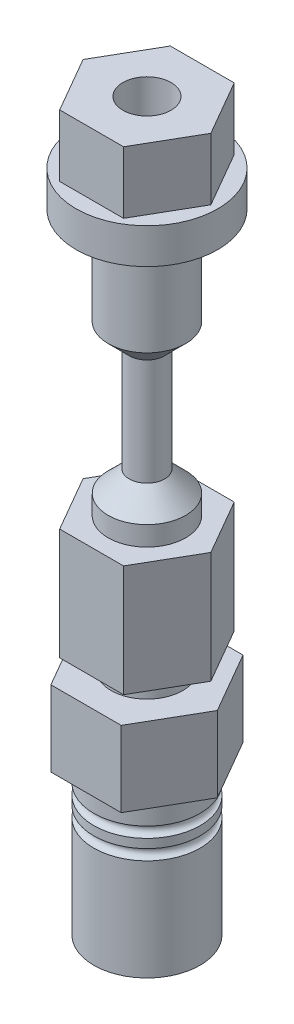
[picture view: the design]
ISO-10303-21;
HEADER;
FILE_DESCRIPTION(('STEP AP214'),'2;1');
FILE_NAME('part.step','',(''),(''),'','','');
FILE_SCHEMA(('AUTOMOTIVE_DESIGN { 1 0 10303 214 1 1 1 1 }'));
ENDSEC;
DATA;
#1=APPLICATION_CONTEXT('core data for automotive mechanical design processes');
#2=APPLICATION_PROTOCOL_DEFINITION('international standard','automotive_design',2000,#1);
#3=PRODUCT_CONTEXT('',#1,'mechanical');
#4=PRODUCT('Part','Part','',(#3));
#5=PRODUCT_RELATED_PRODUCT_CATEGORY('part','',(#4));
#6=PRODUCT_DEFINITION_FORMATION('','',#4);
#7=PRODUCT_DEFINITION_CONTEXT('part definition',#1,'design');
#8=PRODUCT_DEFINITION('design','',#6,#7);
#9=PRODUCT_DEFINITION_SHAPE('','',#8);
#10=(LENGTH_UNIT() NAMED_UNIT(*) SI_UNIT(.MILLI.,.METRE.));
#11=(NAMED_UNIT(*) PLANE_ANGLE_UNIT() SI_UNIT($,.RADIAN.));
#12=(NAMED_UNIT(*) SI_UNIT($,.STERADIAN.) SOLID_ANGLE_UNIT());
#13=UNCERTAINTY_MEASURE_WITH_UNIT(LENGTH_MEASURE(1.E-05),#10,'distance_accuracy_value','');
#14=(GEOMETRIC_REPRESENTATION_CONTEXT(3) GLOBAL_UNCERTAINTY_ASSIGNED_CONTEXT((#13)) GLOBAL_UNIT_ASSIGNED_CONTEXT((#10,
#11,#12)) REPRESENTATION_CONTEXT('',''));
#15=CARTESIAN_POINT('',(0.,0.,0.));
#16=DIRECTION('',(0.,0.,1.));
#17=DIRECTION('',(1.,0.,0.));
#18=AXIS2_PLACEMENT_3D('',#15,#16,#17);
#19=CARTESIAN_POINT('',(9.16543552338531,-59.182,0.));
#20=DIRECTION('',(-0.866025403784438,0.,-0.5));
#21=DIRECTION('',(-0.5,0.,0.866025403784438));
#22=AXIS2_PLACEMENT_3D('',#19,#20,#21);
#23=PLANE('',#22);
#24=DIRECTION('',(-0.5,0.,0.866025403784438));
#25=VECTOR('',#24,1.);
#26=CARTESIAN_POINT('',(9.16543552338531,-43.18,0.));
#27=LINE('',#26,#25);
#28=CARTESIAN_POINT('',(9.16543552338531,-43.18,0.));
#29=VERTEX_POINT('',#28);
#30=CARTESIAN_POINT('',(4.58271776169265,-43.18,7.9375));
#31=VERTEX_POINT('',#30);
#32=EDGE_CURVE('E135',#29,#31,#27,.T.);
#33=ORIENTED_EDGE('',*,*,#32,.T.);
#34=DIRECTION('',(0.,1.,0.));
#35=VECTOR('',#34,1.);
#36=CARTESIAN_POINT('',(4.58271776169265,-59.182,7.9375));
#37=LINE('',#36,#35);
#38=CARTESIAN_POINT('',(4.58271776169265,-59.182,7.9375));
#39=VERTEX_POINT('',#38);
#40=EDGE_CURVE('E153',#39,#31,#37,.T.);
#41=ORIENTED_EDGE('',*,*,#40,.F.);
#42=DIRECTION('',(-0.5,0.,0.866025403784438));
#43=VECTOR('',#42,1.);
#44=CARTESIAN_POINT('',(9.16543552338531,-59.182,0.));
#45=LINE('',#44,#43);
#46=CARTESIAN_POINT('',(9.16543552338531,-59.182,0.));
#47=VERTEX_POINT('',#46);
#48=EDGE_CURVE('E146',#47,#39,#45,.T.);
#49=ORIENTED_EDGE('',*,*,#48,.F.);
#50=DIRECTION('',(0.,1.,0.));
#51=VECTOR('',#50,1.);
#52=CARTESIAN_POINT('',(9.16543552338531,-59.182,0.));
#53=LINE('',#52,#51);
#54=EDGE_CURVE('E131',#47,#29,#53,.T.);
#55=ORIENTED_EDGE('',*,*,#54,.T.);
#56=EDGE_LOOP('',(#33,#41,#49,#55));
#57=FACE_BOUND('',#56,.T.);
#58=ADVANCED_FACE('F45',(#57),#23,.F.);
#59=CARTESIAN_POINT('',(4.58271776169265,-59.182,7.9375));
#60=DIRECTION('',(0.,0.,-1.));
#61=DIRECTION('',(-1.,0.,0.));
#62=AXIS2_PLACEMENT_3D('',#59,#60,#61);
#63=PLANE('',#62);
#64=DIRECTION('',(-1.,0.,0.));
#65=VECTOR('',#64,1.);
#66=CARTESIAN_POINT('',(4.58271776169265,-43.18,7.9375));
#67=LINE('',#66,#65);
#68=CARTESIAN_POINT('',(-4.58271776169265,-43.18,7.9375));
#69=VERTEX_POINT('',#68);
#70=EDGE_CURVE('E138',#31,#69,#67,.T.);
#71=ORIENTED_EDGE('',*,*,#70,.T.);
#72=DIRECTION('',(0.,1.,0.));
#73=VECTOR('',#72,1.);
#74=CARTESIAN_POINT('',(-4.58271776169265,-59.182,7.9375));
#75=LINE('',#74,#73);
#76=CARTESIAN_POINT('',(-4.58271776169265,-59.182,7.9375));
#77=VERTEX_POINT('',#76);
#78=EDGE_CURVE('E150',#77,#69,#75,.T.);
#79=ORIENTED_EDGE('',*,*,#78,.F.);
#80=DIRECTION('',(-1.,0.,0.));
#81=VECTOR('',#80,1.);
#82=CARTESIAN_POINT('',(4.58271776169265,-59.182,7.9375));
#83=LINE('',#82,#81);
#84=EDGE_CURVE('E101',#39,#77,#83,.T.);
#85=ORIENTED_EDGE('',*,*,#84,.F.);
#86=ORIENTED_EDGE('',*,*,#40,.T.);
#87=EDGE_LOOP('',(#71,#79,#85,#86));
#88=FACE_BOUND('',#87,.T.);
#89=ADVANCED_FACE('F174',(#88),#63,.F.);
#90=CARTESIAN_POINT('',(-4.58271776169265,-59.182,7.9375));
#91=DIRECTION('',(0.866025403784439,0.,-0.5));
#92=DIRECTION('',(-0.5,0.,-0.866025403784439));
#93=AXIS2_PLACEMENT_3D('',#90,#91,#92);
#94=PLANE('',#93);
#95=DIRECTION('',(-0.5,0.,-0.866025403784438));
#96=VECTOR('',#95,1.);
#97=CARTESIAN_POINT('',(-4.58271776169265,-43.18,7.9375));
#98=LINE('',#97,#96);
#99=CARTESIAN_POINT('',(-9.16543552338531,-43.18,0.));
#100=VERTEX_POINT('',#99);
#101=EDGE_CURVE('E141',#69,#100,#98,.T.);
#102=ORIENTED_EDGE('',*,*,#101,.T.);
#103=DIRECTION('',(0.,1.,0.));
#104=VECTOR('',#103,1.);
#105=CARTESIAN_POINT('',(-9.16543552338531,-59.182,0.));
#106=LINE('',#105,#104);
#107=CARTESIAN_POINT('',(-9.16543552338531,-59.182,0.));
#108=VERTEX_POINT('',#107);
#109=EDGE_CURVE('E126',#108,#100,#106,.T.);
#110=ORIENTED_EDGE('',*,*,#109,.F.);
#111=DIRECTION('',(-0.5,0.,-0.866025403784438));
#112=VECTOR('',#111,1.);
#113=CARTESIAN_POINT('',(-4.58271776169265,-59.182,7.9375));
#114=LINE('',#113,#112);
#115=EDGE_CURVE('E117',#77,#108,#114,.T.);
#116=ORIENTED_EDGE('',*,*,#115,.F.);
#117=ORIENTED_EDGE('',*,*,#78,.T.);
#118=EDGE_LOOP('',(#102,#110,#116,#117));
#119=FACE_BOUND('',#118,.T.);
#120=ADVANCED_FACE('F179',(#119),#94,.F.);
#121=CARTESIAN_POINT('',(-9.16543552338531,-59.182,0.));
#122=DIRECTION('',(0.866025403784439,0.,0.5));
#123=DIRECTION('',(0.5,0.,-0.866025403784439));
#124=AXIS2_PLACEMENT_3D('',#121,#122,#123);
#125=PLANE('',#124);
#126=DIRECTION('',(0.5,0.,-0.866025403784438));
#127=VECTOR('',#126,1.);
#128=CARTESIAN_POINT('',(-9.16543552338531,-43.18,0.));
#129=LINE('',#128,#127);
#130=CARTESIAN_POINT('',(-4.58271776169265,-43.18,-7.93749999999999));
#131=VERTEX_POINT('',#130);
#132=EDGE_CURVE('E125',#100,#131,#129,.T.);
#133=ORIENTED_EDGE('',*,*,#132,.T.);
#134=DIRECTION('',(0.,1.,0.));
#135=VECTOR('',#134,1.);
#136=CARTESIAN_POINT('',(-4.58271776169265,-59.182,-7.93749999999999));
#137=LINE('',#136,#135);
#138=CARTESIAN_POINT('',(-4.58271776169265,-59.182,-7.93749999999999));
#139=VERTEX_POINT('',#138);
#140=EDGE_CURVE('E122',#139,#131,#137,.T.);
#141=ORIENTED_EDGE('',*,*,#140,.F.);
#142=DIRECTION('',(0.5,0.,-0.866025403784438));
#143=VECTOR('',#142,1.);
#144=CARTESIAN_POINT('',(-9.16543552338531,-59.182,0.));
#145=LINE('',#144,#143);
#146=EDGE_CURVE('E111',#108,#139,#145,.T.);
#147=ORIENTED_EDGE('',*,*,#146,.F.);
#148=ORIENTED_EDGE('',*,*,#109,.T.);
#149=EDGE_LOOP('',(#133,#141,#147,#148));
#150=FACE_BOUND('',#149,.T.);
#151=ADVANCED_FACE('F123',(#150),#125,.F.);
#152=CARTESIAN_POINT('',(-4.58271776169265,-59.182,-7.93749999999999));
#153=DIRECTION('',(0.,0.,1.));
#154=DIRECTION('',(1.,0.,0.));
#155=AXIS2_PLACEMENT_3D('',#152,#153,#154);
#156=PLANE('',#155);
#157=DIRECTION('',(1.,0.,0.));
#158=VECTOR('',#157,1.);
#159=CARTESIAN_POINT('',(-4.58271776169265,-43.18,-7.93749999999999));
#160=LINE('',#159,#158);
#161=CARTESIAN_POINT('',(4.58271776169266,-43.18,-7.93749999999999));
#162=VERTEX_POINT('',#161);
#163=EDGE_CURVE('E86',#131,#162,#160,.T.);
#164=ORIENTED_EDGE('',*,*,#163,.T.);
#165=DIRECTION('',(0.,1.,0.));
#166=VECTOR('',#165,1.);
#167=CARTESIAN_POINT('',(4.58271776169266,-59.182,-7.93749999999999));
#168=LINE('',#167,#166);
#169=CARTESIAN_POINT('',(4.58271776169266,-59.182,-7.93749999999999));
#170=VERTEX_POINT('',#169);
#171=EDGE_CURVE('E127',#170,#162,#168,.T.);
#172=ORIENTED_EDGE('',*,*,#171,.F.);
#173=DIRECTION('',(1.,0.,0.));
#174=VECTOR('',#173,1.);
#175=CARTESIAN_POINT('',(-4.58271776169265,-59.182,-7.93749999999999));
#176=LINE('',#175,#174);
#177=EDGE_CURVE('E115',#139,#170,#176,.T.);
#178=ORIENTED_EDGE('',*,*,#177,.F.);
#179=ORIENTED_EDGE('',*,*,#140,.T.);
#180=EDGE_LOOP('',(#164,#172,#178,#179));
#181=FACE_BOUND('',#180,.T.);
#182=ADVANCED_FACE('F129',(#181),#156,.F.);
#183=CARTESIAN_POINT('',(4.58271776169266,-59.182,-7.93749999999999));
#184=DIRECTION('',(-0.866025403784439,0.,0.5));
#185=DIRECTION('',(0.5,0.,0.866025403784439));
#186=AXIS2_PLACEMENT_3D('',#183,#184,#185);
#187=PLANE('',#186);
#188=DIRECTION('',(0.5,0.,0.866025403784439));
#189=VECTOR('',#188,1.);
#190=CARTESIAN_POINT('',(4.58271776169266,-43.18,-7.93749999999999));
#191=LINE('',#190,#189);
#192=EDGE_CURVE('E92',#162,#29,#191,.T.);
#193=ORIENTED_EDGE('',*,*,#192,.T.);
#194=ORIENTED_EDGE('',*,*,#54,.F.);
#195=DIRECTION('',(0.5,0.,0.866025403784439));
#196=VECTOR('',#195,1.);
#197=CARTESIAN_POINT('',(4.58271776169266,-59.182,-7.93749999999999));
#198=LINE('',#197,#196);
#199=EDGE_CURVE('E62',#170,#47,#198,.T.);
#200=ORIENTED_EDGE('',*,*,#199,.F.);
#201=ORIENTED_EDGE('',*,*,#171,.T.);
#202=EDGE_LOOP('',(#193,#194,#200,#201));
#203=FACE_BOUND('',#202,.T.);
#204=ADVANCED_FACE('F163',(#203),#187,.F.);
#205=CARTESIAN_POINT('',(0.,-59.182,0.));
#206=DIRECTION('',(0.,-1.,0.));
#207=DIRECTION('',(0.,0.,-1.));
#208=AXIS2_PLACEMENT_3D('',#205,#206,#207);
#209=PLANE('',#208);
#210=CARTESIAN_POINT('',(0.,-59.182,0.));
#211=DIRECTION('',(0.,-1.,0.));
#212=DIRECTION('',(0.,0.,-1.));
#213=AXIS2_PLACEMENT_3D('',#210,#211,#212);
#214=CIRCLE('',#213,5.04464607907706);
#215=CARTESIAN_POINT('',(0.,-59.182,-5.04464607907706));
#216=VERTEX_POINT('',#215);
#217=EDGE_CURVE('E54',#216,#216,#214,.T.);
#218=ORIENTED_EDGE('',*,*,#217,.F.);
#219=EDGE_LOOP('',(#218));
#220=FACE_BOUND('',#219,.T.);
#221=ORIENTED_EDGE('',*,*,#48,.T.);
#222=ORIENTED_EDGE('',*,*,#84,.T.);
#223=ORIENTED_EDGE('',*,*,#115,.T.);
#224=ORIENTED_EDGE('',*,*,#146,.T.);
#225=ORIENTED_EDGE('',*,*,#177,.T.);
#226=ORIENTED_EDGE('',*,*,#199,.T.);
#227=EDGE_LOOP('',(#221,#222,#223,#224,#225,#226));
#228=FACE_BOUND('',#227,.T.);
#229=ADVANCED_FACE('F113',(#220,#228),#209,.T.);
#230=CARTESIAN_POINT('',(0.,-43.18,0.));
#231=DIRECTION('',(0.,-1.,0.));
#232=DIRECTION('',(0.,0.,-1.));
#233=AXIS2_PLACEMENT_3D('',#230,#231,#232);
#234=PLANE('',#233);
#235=CARTESIAN_POINT('',(0.,-43.18,0.));
#236=DIRECTION('',(0.,-1.,0.));
#237=DIRECTION('',(0.,0.,-1.));
#238=AXIS2_PLACEMENT_3D('',#235,#236,#237);
#239=CIRCLE('',#238,1.27);
#240=CARTESIAN_POINT('',(0.,-43.18,-1.27));
#241=VERTEX_POINT('',#240);
#242=EDGE_CURVE('E48',#241,#241,#239,.T.);
#243=ORIENTED_EDGE('',*,*,#242,.T.);
#244=EDGE_LOOP('',(#243));
#245=FACE_BOUND('',#244,.T.);
#246=ORIENTED_EDGE('',*,*,#32,.F.);
#247=ORIENTED_EDGE('',*,*,#192,.F.);
#248=ORIENTED_EDGE('',*,*,#163,.F.);
#249=ORIENTED_EDGE('',*,*,#132,.F.);
#250=ORIENTED_EDGE('',*,*,#101,.F.);
#251=ORIENTED_EDGE('',*,*,#70,.F.);
#252=EDGE_LOOP('',(#246,#247,#248,#249,#250,#251));
#253=FACE_BOUND('',#252,.T.);
#254=ADVANCED_FACE('F162',(#245,#253),#234,.F.);
#255=CARTESIAN_POINT('',(0.,-51.6300631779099,0.));
#256=DIRECTION('',(0.,-1.,0.));
#257=DIRECTION('',(0.,0.,-1.));
#258=AXIS2_PLACEMENT_3D('',#255,#256,#257);
#259=CONICAL_SURFACE('',#258,4.80951582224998,0.0311250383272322);
#260=ORIENTED_EDGE('',*,*,#217,.T.);
#261=EDGE_LOOP('',(#260));
#262=FACE_BOUND('',#261,.T.);
#263=CARTESIAN_POINT('',(0.,-62.357,0.));
#264=DIRECTION('',(0.,-1.,0.));
#265=DIRECTION('',(0.,0.,-1.));
#266=AXIS2_PLACEMENT_3D('',#263,#264,#265);
#267=CIRCLE('',#266,5.1435);
#268=CARTESIAN_POINT('',(0.,-62.357,-5.1435));
#269=VERTEX_POINT('',#268);
#270=EDGE_CURVE('E139',#269,#269,#267,.F.);
#271=ORIENTED_EDGE('',*,*,#270,.T.);
#272=EDGE_LOOP('',(#271));
#273=FACE_BOUND('',#272,.T.);
#274=ADVANCED_FACE('F158',(#262,#273),#259,.T.);
#275=CARTESIAN_POINT('',(10.0893114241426,-73.2028,0.));
#276=DIRECTION('',(-0.866025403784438,0.,-0.5));
#277=DIRECTION('',(-0.5,0.,0.866025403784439));
#278=AXIS2_PLACEMENT_3D('',#275,#276,#277);
#279=PLANE('',#278);
#280=DIRECTION('',(-0.5,0.,0.866025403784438));
#281=VECTOR('',#280,1.);
#282=CARTESIAN_POINT('',(10.0893114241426,-62.357,0.));
#283=LINE('',#282,#281);
#284=CARTESIAN_POINT('',(10.0893114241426,-62.357,0.));
#285=VERTEX_POINT('',#284);
#286=CARTESIAN_POINT('',(5.04465571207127,-62.357,8.7376));
#287=VERTEX_POINT('',#286);
#288=EDGE_CURVE('E226',#285,#287,#283,.T.);
#289=ORIENTED_EDGE('',*,*,#288,.T.);
#290=DIRECTION('',(0.,1.,0.));
#291=VECTOR('',#290,1.);
#292=CARTESIAN_POINT('',(5.04465571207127,-73.2028,8.7376));
#293=LINE('',#292,#291);
#294=CARTESIAN_POINT('',(5.04465571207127,-73.2028,8.7376));
#295=VERTEX_POINT('',#294);
#296=EDGE_CURVE('E191',#295,#287,#293,.T.);
#297=ORIENTED_EDGE('',*,*,#296,.F.);
#298=DIRECTION('',(-0.5,0.,0.866025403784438));
#299=VECTOR('',#298,1.);
#300=CARTESIAN_POINT('',(10.0893114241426,-73.2028,0.));
#301=LINE('',#300,#299);
#302=CARTESIAN_POINT('',(10.0893114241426,-73.2028,0.));
#303=VERTEX_POINT('',#302);
#304=EDGE_CURVE('E213',#303,#295,#301,.T.);
#305=ORIENTED_EDGE('',*,*,#304,.F.);
#306=DIRECTION('',(0.,1.,0.));
#307=VECTOR('',#306,1.);
#308=CARTESIAN_POINT('',(10.0893114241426,-73.2028,0.));
#309=LINE('',#308,#307);
#310=EDGE_CURVE('E206',#303,#285,#309,.T.);
#311=ORIENTED_EDGE('',*,*,#310,.T.);
#312=EDGE_LOOP('',(#289,#297,#305,#311));
#313=FACE_BOUND('',#312,.T.);
#314=ADVANCED_FACE('F328',(#313),#279,.F.);
#315=CARTESIAN_POINT('',(5.04465571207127,-73.2028,8.7376));
#316=DIRECTION('',(0.,0.,-1.));
#317=DIRECTION('',(-1.,0.,0.));
#318=AXIS2_PLACEMENT_3D('',#315,#316,#317);
#319=PLANE('',#318);
#320=DIRECTION('',(-1.,0.,0.));
#321=VECTOR('',#320,1.);
#322=CARTESIAN_POINT('',(5.04465571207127,-62.357,8.7376));
#323=LINE('',#322,#321);
#324=CARTESIAN_POINT('',(-5.04465571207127,-62.357,8.73760000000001));
#325=VERTEX_POINT('',#324);
#326=EDGE_CURVE('E223',#287,#325,#323,.T.);
#327=ORIENTED_EDGE('',*,*,#326,.T.);
#328=DIRECTION('',(0.,1.,0.));
#329=VECTOR('',#328,1.);
#330=CARTESIAN_POINT('',(-5.04465571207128,-73.2028,8.73760000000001));
#331=LINE('',#330,#329);
#332=CARTESIAN_POINT('',(-5.04465571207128,-73.2028,8.73760000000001));
#333=VERTEX_POINT('',#332);
#334=EDGE_CURVE('E194',#333,#325,#331,.T.);
#335=ORIENTED_EDGE('',*,*,#334,.F.);
#336=DIRECTION('',(-1.,0.,0.));
#337=VECTOR('',#336,1.);
#338=CARTESIAN_POINT('',(5.04465571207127,-73.2028,8.7376));
#339=LINE('',#338,#337);
#340=EDGE_CURVE('E241',#295,#333,#339,.T.);
#341=ORIENTED_EDGE('',*,*,#340,.F.);
#342=ORIENTED_EDGE('',*,*,#296,.T.);
#343=EDGE_LOOP('',(#327,#335,#341,#342));
#344=FACE_BOUND('',#343,.T.);
#345=ADVANCED_FACE('F324',(#344),#319,.F.);
#346=CARTESIAN_POINT('',(-5.04465571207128,-73.2028,8.73760000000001));
#347=DIRECTION('',(0.866025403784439,0.,-0.5));
#348=DIRECTION('',(-0.5,0.,-0.866025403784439));
#349=AXIS2_PLACEMENT_3D('',#346,#347,#348);
#350=PLANE('',#349);
#351=DIRECTION('',(-0.5,0.,-0.866025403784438));
#352=VECTOR('',#351,1.);
#353=CARTESIAN_POINT('',(-5.04465571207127,-62.357,8.73760000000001));
#354=LINE('',#353,#352);
#355=CARTESIAN_POINT('',(-10.0893114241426,-62.357,0.));
#356=VERTEX_POINT('',#355);
#357=EDGE_CURVE('E220',#325,#356,#354,.T.);
#358=ORIENTED_EDGE('',*,*,#357,.T.);
#359=DIRECTION('',(0.,1.,0.));
#360=VECTOR('',#359,1.);
#361=CARTESIAN_POINT('',(-10.0893114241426,-73.2028,0.));
#362=LINE('',#361,#360);
#363=CARTESIAN_POINT('',(-10.0893114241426,-73.2028,0.));
#364=VERTEX_POINT('',#363);
#365=EDGE_CURVE('E197',#364,#356,#362,.T.);
#366=ORIENTED_EDGE('',*,*,#365,.F.);
#367=DIRECTION('',(-0.5,0.,-0.866025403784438));
#368=VECTOR('',#367,1.);
#369=CARTESIAN_POINT('',(-5.04465571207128,-73.2028,8.73760000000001));
#370=LINE('',#369,#368);
#371=EDGE_CURVE('E238',#333,#364,#370,.T.);
#372=ORIENTED_EDGE('',*,*,#371,.F.);
#373=ORIENTED_EDGE('',*,*,#334,.T.);
#374=EDGE_LOOP('',(#358,#366,#372,#373));
#375=FACE_BOUND('',#374,.T.);
#376=ADVANCED_FACE('F320',(#375),#350,.F.);
#377=CARTESIAN_POINT('',(-10.0893114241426,-73.2028,0.));
#378=DIRECTION('',(0.866025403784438,0.,0.5));
#379=DIRECTION('',(0.5,0.,-0.866025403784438));
#380=AXIS2_PLACEMENT_3D('',#377,#378,#379);
#381=PLANE('',#380);
#382=DIRECTION('',(0.5,0.,-0.866025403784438));
#383=VECTOR('',#382,1.);
#384=CARTESIAN_POINT('',(-10.0893114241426,-62.357,0.));
#385=LINE('',#384,#383);
#386=CARTESIAN_POINT('',(-5.04465571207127,-62.357,-8.7376));
#387=VERTEX_POINT('',#386);
#388=EDGE_CURVE('E217',#356,#387,#385,.T.);
#389=ORIENTED_EDGE('',*,*,#388,.T.);
#390=DIRECTION('',(0.,1.,0.));
#391=VECTOR('',#390,1.);
#392=CARTESIAN_POINT('',(-5.04465571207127,-73.2028,-8.7376));
#393=LINE('',#392,#391);
#394=CARTESIAN_POINT('',(-5.04465571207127,-73.2028,-8.7376));
#395=VERTEX_POINT('',#394);
#396=EDGE_CURVE('E200',#395,#387,#393,.T.);
#397=ORIENTED_EDGE('',*,*,#396,.F.);
#398=DIRECTION('',(0.5,0.,-0.866025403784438));
#399=VECTOR('',#398,1.);
#400=CARTESIAN_POINT('',(-10.0893114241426,-73.2028,0.));
#401=LINE('',#400,#399);
#402=EDGE_CURVE('E235',#364,#395,#401,.T.);
#403=ORIENTED_EDGE('',*,*,#402,.F.);
#404=ORIENTED_EDGE('',*,*,#365,.T.);
#405=EDGE_LOOP('',(#389,#397,#403,#404));
#406=FACE_BOUND('',#405,.T.);
#407=ADVANCED_FACE('F316',(#406),#381,.F.);
#408=CARTESIAN_POINT('',(-5.04465571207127,-73.2028,-8.7376));
#409=DIRECTION('',(0.,0.,1.));
#410=DIRECTION('',(1.,0.,0.));
#411=AXIS2_PLACEMENT_3D('',#408,#409,#410);
#412=PLANE('',#411);
#413=DIRECTION('',(1.,0.,0.));
#414=VECTOR('',#413,1.);
#415=CARTESIAN_POINT('',(-5.04465571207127,-62.357,-8.7376));
#416=LINE('',#415,#414);
#417=CARTESIAN_POINT('',(5.04465571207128,-62.357,-8.7376));
#418=VERTEX_POINT('',#417);
#419=EDGE_CURVE('E214',#387,#418,#416,.T.);
#420=ORIENTED_EDGE('',*,*,#419,.T.);
#421=DIRECTION('',(0.,1.,0.));
#422=VECTOR('',#421,1.);
#423=CARTESIAN_POINT('',(5.04465571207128,-73.2028,-8.7376));
#424=LINE('',#423,#422);
#425=CARTESIAN_POINT('',(5.04465571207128,-73.2028,-8.7376));
#426=VERTEX_POINT('',#425);
#427=EDGE_CURVE('E203',#426,#418,#424,.T.);
#428=ORIENTED_EDGE('',*,*,#427,.F.);
#429=DIRECTION('',(1.,0.,0.));
#430=VECTOR('',#429,1.);
#431=CARTESIAN_POINT('',(-5.04465571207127,-73.2028,-8.7376));
#432=LINE('',#431,#430);
#433=EDGE_CURVE('E232',#395,#426,#432,.T.);
#434=ORIENTED_EDGE('',*,*,#433,.F.);
#435=ORIENTED_EDGE('',*,*,#396,.T.);
#436=EDGE_LOOP('',(#420,#428,#434,#435));
#437=FACE_BOUND('',#436,.T.);
#438=ADVANCED_FACE('F312',(#437),#412,.F.);
#439=CARTESIAN_POINT('',(5.04465571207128,-73.2028,-8.7376));
#440=DIRECTION('',(-0.866025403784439,0.,0.5));
#441=DIRECTION('',(0.5,0.,0.866025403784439));
#442=AXIS2_PLACEMENT_3D('',#439,#440,#441);
#443=PLANE('',#442);
#444=DIRECTION('',(0.5,0.,0.866025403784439));
#445=VECTOR('',#444,1.);
#446=CARTESIAN_POINT('',(5.04465571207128,-62.357,-8.7376));
#447=LINE('',#446,#445);
#448=EDGE_CURVE('E210',#418,#285,#447,.T.);
#449=ORIENTED_EDGE('',*,*,#448,.T.);
#450=ORIENTED_EDGE('',*,*,#310,.F.);
#451=DIRECTION('',(0.5,0.,0.866025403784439));
#452=VECTOR('',#451,1.);
#453=CARTESIAN_POINT('',(5.04465571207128,-73.2028,-8.7376));
#454=LINE('',#453,#452);
#455=EDGE_CURVE('E209',#426,#303,#454,.T.);
#456=ORIENTED_EDGE('',*,*,#455,.F.);
#457=ORIENTED_EDGE('',*,*,#427,.T.);
#458=EDGE_LOOP('',(#449,#450,#456,#457));
#459=FACE_BOUND('',#458,.T.);
#460=ADVANCED_FACE('F305',(#459),#443,.F.);
#461=CARTESIAN_POINT('',(0.,-73.2028,0.));
#462=DIRECTION('',(0.,-1.,0.));
#463=DIRECTION('',(0.,0.,-1.));
#464=AXIS2_PLACEMENT_3D('',#461,#462,#463);
#465=PLANE('',#464);
#466=CARTESIAN_POINT('',(0.,-73.2028,0.));
#467=DIRECTION('',(0.,-1.,0.));
#468=DIRECTION('',(0.,0.,-1.));
#469=AXIS2_PLACEMENT_3D('',#466,#467,#468);
#470=CIRCLE('',#469,7.62);
#471=CARTESIAN_POINT('',(0.,-73.2028,-7.62));
#472=VERTEX_POINT('',#471);
#473=EDGE_CURVE('E12',#472,#472,#470,.T.);
#474=ORIENTED_EDGE('',*,*,#473,.F.);
#475=EDGE_LOOP('',(#474));
#476=FACE_BOUND('',#475,.T.);
#477=ORIENTED_EDGE('',*,*,#304,.T.);
#478=ORIENTED_EDGE('',*,*,#340,.T.);
#479=ORIENTED_EDGE('',*,*,#371,.T.);
#480=ORIENTED_EDGE('',*,*,#402,.T.);
#481=ORIENTED_EDGE('',*,*,#433,.T.);
#482=ORIENTED_EDGE('',*,*,#455,.T.);
#483=EDGE_LOOP('',(#477,#478,#479,#480,#481,#482));
#484=FACE_BOUND('',#483,.T.);
#485=ADVANCED_FACE('F302',(#476,#484),#465,.T.);
#486=CARTESIAN_POINT('',(0.,-62.357,0.));
#487=DIRECTION('',(0.,-1.,0.));
#488=DIRECTION('',(0.,0.,-1.));
#489=AXIS2_PLACEMENT_3D('',#486,#487,#488);
#490=PLANE('',#489);
#491=ORIENTED_EDGE('',*,*,#270,.F.);
#492=EDGE_LOOP('',(#491));
#493=FACE_BOUND('',#492,.T.);
#494=ORIENTED_EDGE('',*,*,#288,.F.);
#495=ORIENTED_EDGE('',*,*,#448,.F.);
#496=ORIENTED_EDGE('',*,*,#419,.F.);
#497=ORIENTED_EDGE('',*,*,#388,.F.);
#498=ORIENTED_EDGE('',*,*,#357,.F.);
#499=ORIENTED_EDGE('',*,*,#326,.F.);
#500=EDGE_LOOP('',(#494,#495,#496,#497,#498,#499));
#501=FACE_BOUND('',#500,.T.);
#502=ADVANCED_FACE('F300',(#493,#501),#490,.F.);
#503=CARTESIAN_POINT('',(0.,-73.2028,0.));
#504=DIRECTION('',(0.,1.,0.));
#505=DIRECTION('',(0.,0.,1.));
#506=AXIS2_PLACEMENT_3D('',#503,#504,#505);
#507=CYLINDRICAL_SURFACE('',#506,7.62);
#508=CARTESIAN_POINT('',(0.,-76.3778,0.));
#509=DIRECTION('',(0.,1.,0.));
#510=DIRECTION('',(0.,0.,1.));
#511=AXIS2_PLACEMENT_3D('',#508,#509,#510);
#512=CIRCLE('',#511,7.62);
#513=CARTESIAN_POINT('',(0.,-76.3778,7.62));
#514=VERTEX_POINT('',#513);
#515=EDGE_CURVE('E229',#514,#514,#512,.T.);
#516=ORIENTED_EDGE('',*,*,#515,.T.);
#517=EDGE_LOOP('',(#516));
#518=FACE_BOUND('',#517,.T.);
#519=ORIENTED_EDGE('',*,*,#473,.T.);
#520=EDGE_LOOP('',(#519));
#521=FACE_BOUND('',#520,.T.);
#522=ADVANCED_FACE('F296',(#518,#521),#507,.T.);
#523=CARTESIAN_POINT('',(0.,-77.1398,0.));
#524=DIRECTION('',(0.,1.,0.));
#525=DIRECTION('',(0.,0.,1.));
#526=AXIS2_PLACEMENT_3D('',#523,#524,#525);
#527=TOROIDAL_SURFACE('',#526,7.62,0.761999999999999);
#528=CARTESIAN_POINT('',(0.,-77.9018,0.));
#529=DIRECTION('',(0.,1.,0.));
#530=DIRECTION('',(0.,0.,1.));
#531=AXIS2_PLACEMENT_3D('',#528,#529,#530);
#532=CIRCLE('',#531,7.62);
#533=CARTESIAN_POINT('',(0.,-77.9018,7.62));
#534=VERTEX_POINT('',#533);
#535=EDGE_CURVE('E248',#534,#534,#532,.T.);
#536=ORIENTED_EDGE('',*,*,#535,.T.);
#537=EDGE_LOOP('',(#536));
#538=FACE_BOUND('',#537,.T.);
#539=ORIENTED_EDGE('',*,*,#515,.F.);
#540=EDGE_LOOP('',(#539));
#541=FACE_BOUND('',#540,.T.);
#542=ADVANCED_FACE('F292',(#538,#541),#527,.F.);
#543=CARTESIAN_POINT('',(0.,-73.2028,0.));
#544=DIRECTION('',(0.,1.,0.));
#545=DIRECTION('',(0.,0.,1.));
#546=AXIS2_PLACEMENT_3D('',#543,#544,#545);
#547=CYLINDRICAL_SURFACE('',#546,7.62);
#548=CARTESIAN_POINT('',(0.,-79.1718,0.));
#549=DIRECTION('',(0.,1.,0.));
#550=DIRECTION('',(0.,0.,1.));
#551=AXIS2_PLACEMENT_3D('',#548,#549,#550);
#552=CIRCLE('',#551,7.62);
#553=CARTESIAN_POINT('',(0.,-79.1718,7.62));
#554=VERTEX_POINT('',#553);
#555=EDGE_CURVE('E251',#554,#554,#552,.T.);
#556=ORIENTED_EDGE('',*,*,#555,.T.);
#557=EDGE_LOOP('',(#556));
#558=FACE_BOUND('',#557,.T.);
#559=ORIENTED_EDGE('',*,*,#535,.F.);
#560=EDGE_LOOP('',(#559));
#561=FACE_BOUND('',#560,.T.);
#562=ADVANCED_FACE('F288',(#558,#561),#547,.T.);
#563=CARTESIAN_POINT('',(0.,-79.9338,0.));
#564=DIRECTION('',(0.,1.,0.));
#565=DIRECTION('',(0.,0.,1.));
#566=AXIS2_PLACEMENT_3D('',#563,#564,#565);
#567=TOROIDAL_SURFACE('',#566,7.62,0.761999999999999);
#568=CARTESIAN_POINT('',(0.,-80.6958,0.));
#569=DIRECTION('',(0.,1.,0.));
#570=DIRECTION('',(0.,0.,1.));
#571=AXIS2_PLACEMENT_3D('',#568,#569,#570);
#572=CIRCLE('',#571,7.62);
#573=CARTESIAN_POINT('',(0.,-80.6958,7.62));
#574=VERTEX_POINT('',#573);
#575=EDGE_CURVE('E254',#574,#574,#572,.T.);
#576=ORIENTED_EDGE('',*,*,#575,.T.);
#577=EDGE_LOOP('',(#576));
#578=FACE_BOUND('',#577,.T.);
#579=ORIENTED_EDGE('',*,*,#555,.F.);
#580=EDGE_LOOP('',(#579));
#581=FACE_BOUND('',#580,.T.);
#582=ADVANCED_FACE('F284',(#578,#581),#567,.F.);
#583=CARTESIAN_POINT('',(0.,-73.2028,0.));
#584=DIRECTION('',(0.,1.,0.));
#585=DIRECTION('',(0.,0.,1.));
#586=AXIS2_PLACEMENT_3D('',#583,#584,#585);
#587=CYLINDRICAL_SURFACE('',#586,7.62);
#588=CARTESIAN_POINT('',(0.,-95.25,0.));
#589=DIRECTION('',(0.,1.,0.));
#590=DIRECTION('',(0.,0.,1.));
#591=AXIS2_PLACEMENT_3D('',#588,#589,#590);
#592=CIRCLE('',#591,7.62);
#593=CARTESIAN_POINT('',(0.,-95.25,7.62));
#594=VERTEX_POINT('',#593);
#595=EDGE_CURVE('E257',#594,#594,#592,.T.);
#596=ORIENTED_EDGE('',*,*,#595,.T.);
#597=EDGE_LOOP('',(#596));
#598=FACE_BOUND('',#597,.T.);
#599=ORIENTED_EDGE('',*,*,#575,.F.);
#600=EDGE_LOOP('',(#599));
#601=FACE_BOUND('',#600,.T.);
#602=ADVANCED_FACE('F278',(#598,#601),#587,.T.);
#603=CARTESIAN_POINT('',(-7.62,-95.25,0.));
#604=DIRECTION('',(0.,-1.,0.));
#605=DIRECTION('',(0.,0.,-1.));
#606=AXIS2_PLACEMENT_3D('',#603,#604,#605);
#607=PLANE('',#606);
#608=ORIENTED_EDGE('',*,*,#595,.F.);
#609=EDGE_LOOP('',(#608));
#610=FACE_BOUND('',#609,.T.);
#611=ADVANCED_FACE('F270',(#610),#607,.T.);
#612=CARTESIAN_POINT('',(0.,15.3585913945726,0.));
#613=DIRECTION('',(0.,1.,0.));
#614=DIRECTION('',(-1.,0.,0.));
#615=AXIS2_PLACEMENT_3D('',#612,#613,#614);
#616=CYLINDRICAL_SURFACE('',#615,1.27);
#617=CARTESIAN_POINT('',(0.,-53.086,0.));
#618=DIRECTION('',(0.,1.,0.));
#619=DIRECTION('',(-1.,0.,0.));
#620=AXIS2_PLACEMENT_3D('',#617,#618,#619);
#621=CIRCLE('',#620,1.27);
#622=CARTESIAN_POINT('',(-1.26999999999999,-53.086,0.));
#623=VERTEX_POINT('',#622);
#624=EDGE_CURVE('E260',#623,#623,#621,.T.);
#625=ORIENTED_EDGE('',*,*,#624,.F.);
#626=EDGE_LOOP('',(#625));
#627=FACE_BOUND('',#626,.T.);
#628=ORIENTED_EDGE('',*,*,#242,.F.);
#629=EDGE_LOOP('',(#628));
#630=FACE_BOUND('',#629,.T.);
#631=ADVANCED_FACE('F267',(#627,#630),#616,.F.);
#632=CARTESIAN_POINT('',(-1.26999999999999,-53.086,0.));
#633=DIRECTION('',(0.,-1.,0.));
#634=DIRECTION('',(1.,0.,0.));
#635=AXIS2_PLACEMENT_3D('',#632,#633,#634);
#636=PLANE('',#635);
#637=ORIENTED_EDGE('',*,*,#624,.T.);
#638=EDGE_LOOP('',(#637));
#639=FACE_BOUND('',#638,.T.);
#640=ADVANCED_FACE('F269',(#639),#636,.F.);
#641=CLOSED_SHELL('',(#58,#89,#120,#151,#182,#204,#229,#254,#274,#314,#345,#376,#407,#438,#460,
#485,#502,#522,#542,#562,#582,#602,#611,#631,#640));
#642=MANIFOLD_SOLID_BREP('B2',#641);
#643=CARTESIAN_POINT('',(0.,0.,0.));
#644=DIRECTION('',(0.,1.,0.));
#645=DIRECTION('',(0.,0.,1.));
#646=AXIS2_PLACEMENT_3D('',#643,#644,#645);
#647=PLANE('',#646);
#648=CARTESIAN_POINT('',(0.,0.,0.));
#649=DIRECTION('',(0.,1.,0.));
#650=DIRECTION('',(0.,0.,1.));
#651=AXIS2_PLACEMENT_3D('',#648,#649,#650);
#652=CIRCLE('',#651,3.4544);
#653=CARTESIAN_POINT('',(0.,0.,3.4544));
#654=VERTEX_POINT('',#653);
#655=EDGE_CURVE('E561',#654,#654,#652,.T.);
#656=ORIENTED_EDGE('',*,*,#655,.F.);
#657=EDGE_LOOP('',(#656));
#658=FACE_BOUND('',#657,.T.);
#659=CARTESIAN_POINT('',(0.,0.,0.));
#660=DIRECTION('',(0.,1.,0.));
#661=DIRECTION('',(0.,0.,1.));
#662=AXIS2_PLACEMENT_3D('',#659,#660,#661);
#663=CIRCLE('',#662,10.16);
#664=CARTESIAN_POINT('',(0.,0.,10.16));
#665=VERTEX_POINT('',#664);
#666=EDGE_CURVE('E44',#665,#665,#663,.T.);
#667=ORIENTED_EDGE('',*,*,#666,.T.);
#668=EDGE_LOOP('',(#667));
#669=FACE_BOUND('',#668,.T.);
#670=ADVANCED_FACE('F546',(#658,#669),#647,.T.);
#671=CARTESIAN_POINT('',(0.,0.,0.));
#672=DIRECTION('',(0.,1.,0.));
#673=DIRECTION('',(0.,0.,1.));
#674=AXIS2_PLACEMENT_3D('',#671,#672,#673);
#675=CYLINDRICAL_SURFACE('',#674,10.16);
#676=CARTESIAN_POINT('',(0.,-5.08,0.));
#677=DIRECTION('',(0.,1.,0.));
#678=DIRECTION('',(0.,0.,1.));
#679=AXIS2_PLACEMENT_3D('',#676,#677,#678);
#680=CIRCLE('',#679,10.16);
#681=CARTESIAN_POINT('',(0.,-5.08,10.16));
#682=VERTEX_POINT('',#681);
#683=EDGE_CURVE('E553',#682,#682,#680,.T.);
#684=ORIENTED_EDGE('',*,*,#683,.T.);
#685=EDGE_LOOP('',(#684));
#686=FACE_BOUND('',#685,.T.);
#687=ORIENTED_EDGE('',*,*,#666,.F.);
#688=EDGE_LOOP('',(#687));
#689=FACE_BOUND('',#688,.T.);
#690=ADVANCED_FACE('F613',(#686,#689),#675,.T.);
#691=CARTESIAN_POINT('',(-10.16,-5.08,0.));
#692=DIRECTION('',(0.,-1.,0.));
#693=DIRECTION('',(0.,0.,-1.));
#694=AXIS2_PLACEMENT_3D('',#691,#692,#693);
#695=PLANE('',#694);
#696=CARTESIAN_POINT('',(0.,-5.08,0.));
#697=DIRECTION('',(0.,1.,0.));
#698=DIRECTION('',(0.,0.,1.));
#699=AXIS2_PLACEMENT_3D('',#696,#697,#698);
#700=CIRCLE('',#699,4.62661);
#701=CARTESIAN_POINT('',(0.,-5.08,4.62661));
#702=VERTEX_POINT('',#701);
#703=EDGE_CURVE('E558',#702,#702,#700,.T.);
#704=ORIENTED_EDGE('',*,*,#703,.T.);
#705=EDGE_LOOP('',(#704));
#706=FACE_BOUND('',#705,.T.);
#707=ORIENTED_EDGE('',*,*,#683,.F.);
#708=EDGE_LOOP('',(#707));
#709=FACE_BOUND('',#708,.T.);
#710=ADVANCED_FACE('F598',(#706,#709),#695,.T.);
#711=CARTESIAN_POINT('',(0.,0.,0.));
#712=DIRECTION('',(0.,1.,0.));
#713=DIRECTION('',(0.,0.,1.));
#714=AXIS2_PLACEMENT_3D('',#711,#712,#713);
#715=CYLINDRICAL_SURFACE('',#714,4.62661);
#716=CARTESIAN_POINT('',(0.,-7.1628,0.));
#717=DIRECTION('',(0.,1.,0.));
#718=DIRECTION('',(0.,0.,1.));
#719=AXIS2_PLACEMENT_3D('',#716,#717,#718);
#720=CIRCLE('',#719,4.62661);
#721=CARTESIAN_POINT('',(0.,-7.1628,4.62661));
#722=VERTEX_POINT('',#721);
#723=EDGE_CURVE('E593',#722,#722,#720,.T.);
#724=ORIENTED_EDGE('',*,*,#723,.T.);
#725=EDGE_LOOP('',(#724));
#726=FACE_BOUND('',#725,.T.);
#727=ORIENTED_EDGE('',*,*,#703,.F.);
#728=EDGE_LOOP('',(#727));
#729=FACE_BOUND('',#728,.T.);
#730=ADVANCED_FACE('F601',(#726,#729),#715,.T.);
#731=CARTESIAN_POINT('',(-4.62661,-7.1628,0.));
#732=DIRECTION('',(0.,1.,0.));
#733=DIRECTION('',(0.,0.,1.));
#734=AXIS2_PLACEMENT_3D('',#731,#732,#733);
#735=PLANE('',#734);
#736=CARTESIAN_POINT('',(0.,-7.1628,0.));
#737=DIRECTION('',(0.,1.,0.));
#738=DIRECTION('',(0.,0.,1.));
#739=AXIS2_PLACEMENT_3D('',#736,#737,#738);
#740=CIRCLE('',#739,5.55625);
#741=CARTESIAN_POINT('',(0.,-7.1628,5.55625));
#742=VERTEX_POINT('',#741);
#743=EDGE_CURVE('E590',#742,#742,#740,.T.);
#744=ORIENTED_EDGE('',*,*,#743,.T.);
#745=EDGE_LOOP('',(#744));
#746=FACE_BOUND('',#745,.T.);
#747=ORIENTED_EDGE('',*,*,#723,.F.);
#748=EDGE_LOOP('',(#747));
#749=FACE_BOUND('',#748,.T.);
#750=ADVANCED_FACE('F603',(#746,#749),#735,.T.);
#751=CARTESIAN_POINT('',(0.,0.,0.));
#752=DIRECTION('',(0.,1.,0.));
#753=DIRECTION('',(0.,0.,1.));
#754=AXIS2_PLACEMENT_3D('',#751,#752,#753);
#755=CYLINDRICAL_SURFACE('',#754,5.55625);
#756=CARTESIAN_POINT('',(0.,-19.05,0.));
#757=DIRECTION('',(0.,1.,0.));
#758=DIRECTION('',(0.,0.,1.));
#759=AXIS2_PLACEMENT_3D('',#756,#757,#758);
#760=CIRCLE('',#759,5.55625);
#761=CARTESIAN_POINT('',(0.,-19.05,5.55625));
#762=VERTEX_POINT('',#761);
#763=EDGE_CURVE('E587',#762,#762,#760,.T.);
#764=ORIENTED_EDGE('',*,*,#763,.T.);
#765=EDGE_LOOP('',(#764));
#766=FACE_BOUND('',#765,.T.);
#767=ORIENTED_EDGE('',*,*,#743,.F.);
#768=EDGE_LOOP('',(#767));
#769=FACE_BOUND('',#768,.T.);
#770=ADVANCED_FACE('F610',(#766,#769),#755,.T.);
#771=CARTESIAN_POINT('',(0.,-19.05,0.));
#772=DIRECTION('',(0.,1.,0.));
#773=DIRECTION('',(0.,0.,1.));
#774=AXIS2_PLACEMENT_3D('',#771,#772,#773);
#775=CONICAL_SURFACE('',#774,5.55625,0.78539816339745);
#776=CARTESIAN_POINT('',(0.,-22.06625,0.));
#777=DIRECTION('',(0.,1.,0.));
#778=DIRECTION('',(0.,0.,1.));
#779=AXIS2_PLACEMENT_3D('',#776,#777,#778);
#780=CIRCLE('',#779,2.54);
#781=CARTESIAN_POINT('',(0.,-22.06625,2.54));
#782=VERTEX_POINT('',#781);
#783=EDGE_CURVE('E584',#782,#782,#780,.T.);
#784=ORIENTED_EDGE('',*,*,#783,.T.);
#785=EDGE_LOOP('',(#784));
#786=FACE_BOUND('',#785,.T.);
#787=ORIENTED_EDGE('',*,*,#763,.F.);
#788=EDGE_LOOP('',(#787));
#789=FACE_BOUND('',#788,.T.);
#790=ADVANCED_FACE('F648',(#786,#789),#775,.T.);
#791=CARTESIAN_POINT('',(0.,0.,0.));
#792=DIRECTION('',(0.,1.,0.));
#793=DIRECTION('',(0.,0.,1.));
#794=AXIS2_PLACEMENT_3D('',#791,#792,#793);
#795=CYLINDRICAL_SURFACE('',#794,2.54);
#796=CARTESIAN_POINT('',(0.,-37.36975,0.));
#797=DIRECTION('',(0.,1.,0.));
#798=DIRECTION('',(0.,0.,1.));
#799=AXIS2_PLACEMENT_3D('',#796,#797,#798);
#800=CIRCLE('',#799,2.54);
#801=CARTESIAN_POINT('',(0.,-37.36975,2.54));
#802=VERTEX_POINT('',#801);
#803=EDGE_CURVE('E581',#802,#802,#800,.T.);
#804=ORIENTED_EDGE('',*,*,#803,.T.);
#805=EDGE_LOOP('',(#804));
#806=FACE_BOUND('',#805,.T.);
#807=ORIENTED_EDGE('',*,*,#783,.F.);
#808=EDGE_LOOP('',(#807));
#809=FACE_BOUND('',#808,.T.);
#810=ADVANCED_FACE('F658',(#806,#809),#795,.T.);
#811=CARTESIAN_POINT('',(0.,-37.36975,0.));
#812=DIRECTION('',(0.,-1.,0.));
#813=DIRECTION('',(0.,0.,-1.));
#814=AXIS2_PLACEMENT_3D('',#811,#812,#813);
#815=CONICAL_SURFACE('',#814,2.54,0.78539816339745);
#816=CARTESIAN_POINT('',(0.,-40.386,0.));
#817=DIRECTION('',(0.,1.,0.));
#818=DIRECTION('',(0.,0.,1.));
#819=AXIS2_PLACEMENT_3D('',#816,#817,#818);
#820=CIRCLE('',#819,5.55624999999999);
#821=CARTESIAN_POINT('',(0.,-40.386,5.55624999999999));
#822=VERTEX_POINT('',#821);
#823=EDGE_CURVE('E568',#822,#822,#820,.T.);
#824=ORIENTED_EDGE('',*,*,#823,.T.);
#825=EDGE_LOOP('',(#824));
#826=FACE_BOUND('',#825,.T.);
#827=ORIENTED_EDGE('',*,*,#803,.F.);
#828=EDGE_LOOP('',(#827));
#829=FACE_BOUND('',#828,.T.);
#830=ADVANCED_FACE('F668',(#826,#829),#815,.T.);
#831=CARTESIAN_POINT('',(0.,0.,0.));
#832=DIRECTION('',(0.,1.,0.));
#833=DIRECTION('',(0.,0.,1.));
#834=AXIS2_PLACEMENT_3D('',#831,#832,#833);
#835=CYLINDRICAL_SURFACE('',#834,5.55624999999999);
#836=CARTESIAN_POINT('',(0.,-53.086,0.));
#837=DIRECTION('',(0.,1.,0.));
#838=DIRECTION('',(0.,0.,1.));
#839=AXIS2_PLACEMENT_3D('',#836,#837,#838);
#840=CIRCLE('',#839,5.55624999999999);
#841=CARTESIAN_POINT('',(0.,-53.086,5.55624999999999));
#842=VERTEX_POINT('',#841);
#843=EDGE_CURVE('E563',#842,#842,#840,.T.);
#844=ORIENTED_EDGE('',*,*,#843,.T.);
#845=EDGE_LOOP('',(#844));
#846=FACE_BOUND('',#845,.T.);
#847=ORIENTED_EDGE('',*,*,#823,.F.);
#848=EDGE_LOOP('',(#847));
#849=FACE_BOUND('',#848,.T.);
#850=ADVANCED_FACE('F678',(#846,#849),#835,.T.);
#851=CARTESIAN_POINT('',(-5.55624999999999,-53.086,0.));
#852=DIRECTION('',(0.,-1.,0.));
#853=DIRECTION('',(0.,0.,-1.));
#854=AXIS2_PLACEMENT_3D('',#851,#852,#853);
#855=PLANE('',#854);
#856=CARTESIAN_POINT('',(0.,-53.086,0.));
#857=DIRECTION('',(0.,1.,0.));
#858=DIRECTION('',(-1.,0.,0.));
#859=AXIS2_PLACEMENT_3D('',#856,#857,#858);
#860=CIRCLE('',#859,1.27);
#861=CARTESIAN_POINT('',(-1.26999999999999,-53.086,0.));
#862=VERTEX_POINT('',#861);
#863=EDGE_CURVE('E780',#862,#862,#860,.T.);
#864=ORIENTED_EDGE('',*,*,#863,.T.);
#865=EDGE_LOOP('',(#864));
#866=FACE_BOUND('',#865,.T.);
#867=ORIENTED_EDGE('',*,*,#843,.F.);
#868=EDGE_LOOP('',(#867));
#869=FACE_BOUND('',#868,.T.);
#870=ADVANCED_FACE('F687',(#866,#869),#855,.T.);
#871=CARTESIAN_POINT('',(0.,-3.81,0.));
#872=DIRECTION('',(0.,1.,0.));
#873=DIRECTION('',(0.,0.,1.));
#874=AXIS2_PLACEMENT_3D('',#871,#872,#873);
#875=CONICAL_SURFACE('',#874,3.4544,1.02974425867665);
#876=CARTESIAN_POINT('',(0.,-4.35179602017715,0.));
#877=DIRECTION('',(0.,1.,0.));
#878=DIRECTION('',(0.,0.,1.));
#879=AXIS2_PLACEMENT_3D('',#876,#877,#878);
#880=CIRCLE('',#879,2.5527);
#881=CARTESIAN_POINT('',(0.,-4.35179602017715,2.5527));
#882=VERTEX_POINT('',#881);
#883=EDGE_CURVE('E549',#882,#882,#880,.F.);
#884=ORIENTED_EDGE('',*,*,#883,.T.);
#885=EDGE_LOOP('',(#884));
#886=FACE_BOUND('',#885,.T.);
#887=CARTESIAN_POINT('',(0.,-3.81,0.));
#888=DIRECTION('',(0.,1.,0.));
#889=DIRECTION('',(0.,0.,1.));
#890=AXIS2_PLACEMENT_3D('',#887,#888,#889);
#891=CIRCLE('',#890,3.4544);
#892=CARTESIAN_POINT('',(0.,-3.81,3.4544));
#893=VERTEX_POINT('',#892);
#894=EDGE_CURVE('E564',#893,#893,#891,.T.);
#895=ORIENTED_EDGE('',*,*,#894,.T.);
#896=EDGE_LOOP('',(#895));
#897=FACE_BOUND('',#896,.T.);
#898=ADVANCED_FACE('F707',(#886,#897),#875,.F.);
#899=CARTESIAN_POINT('',(0.,8.89,0.));
#900=DIRECTION('',(0.,1.,0.));
#901=DIRECTION('',(0.,0.,1.));
#902=AXIS2_PLACEMENT_3D('',#899,#900,#901);
#903=CYLINDRICAL_SURFACE('',#902,3.4544);
#904=ORIENTED_EDGE('',*,*,#655,.T.);
#905=EDGE_LOOP('',(#904));
#906=FACE_BOUND('',#905,.T.);
#907=ORIENTED_EDGE('',*,*,#894,.F.);
#908=EDGE_LOOP('',(#907));
#909=FACE_BOUND('',#908,.T.);
#910=ADVANCED_FACE('F700',(#906,#909),#903,.F.);
#911=CARTESIAN_POINT('',(0.,15.3585913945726,0.));
#912=DIRECTION('',(0.,1.,0.));
#913=DIRECTION('',(-1.,0.,0.));
#914=AXIS2_PLACEMENT_3D('',#911,#912,#913);
#915=CYLINDRICAL_SURFACE('',#914,2.5527);
#916=CARTESIAN_POINT('',(0.,-16.51,0.));
#917=DIRECTION('',(0.,1.,0.));
#918=DIRECTION('',(-1.,0.,0.));
#919=AXIS2_PLACEMENT_3D('',#916,#917,#918);
#920=CIRCLE('',#919,2.5527);
#921=CARTESIAN_POINT('',(-2.5527,-16.51,0.));
#922=VERTEX_POINT('',#921);
#923=EDGE_CURVE('E575',#922,#922,#920,.T.);
#924=ORIENTED_EDGE('',*,*,#923,.F.);
#925=EDGE_LOOP('',(#924));
#926=FACE_BOUND('',#925,.T.);
#927=ORIENTED_EDGE('',*,*,#883,.F.);
#928=EDGE_LOOP('',(#927));
#929=FACE_BOUND('',#928,.T.);
#930=ADVANCED_FACE('F706',(#926,#929),#915,.F.);
#931=CARTESIAN_POINT('',(-2.5527,-16.51,0.));
#932=DIRECTION('',(0.,-1.,0.));
#933=DIRECTION('',(1.,0.,0.));
#934=AXIS2_PLACEMENT_3D('',#931,#932,#933);
#935=PLANE('',#934);
#936=CARTESIAN_POINT('',(0.,-16.51,0.));
#937=DIRECTION('',(0.,1.,0.));
#938=DIRECTION('',(-1.,0.,0.));
#939=AXIS2_PLACEMENT_3D('',#936,#937,#938);
#940=CIRCLE('',#939,1.5875);
#941=CARTESIAN_POINT('',(-1.5875,-16.51,0.));
#942=VERTEX_POINT('',#941);
#943=EDGE_CURVE('E787',#942,#942,#940,.T.);
#944=ORIENTED_EDGE('',*,*,#943,.F.);
#945=EDGE_LOOP('',(#944));
#946=FACE_BOUND('',#945,.T.);
#947=ORIENTED_EDGE('',*,*,#923,.T.);
#948=EDGE_LOOP('',(#947));
#949=FACE_BOUND('',#948,.T.);
#950=ADVANCED_FACE('F733',(#946,#949),#935,.F.);
#951=CARTESIAN_POINT('',(0.,15.3585913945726,0.));
#952=DIRECTION('',(0.,1.,0.));
#953=DIRECTION('',(-1.,0.,0.));
#954=AXIS2_PLACEMENT_3D('',#951,#952,#953);
#955=CYLINDRICAL_SURFACE('',#954,1.5875);
#956=CARTESIAN_POINT('',(0.,-36.83,0.));
#957=DIRECTION('',(0.,1.,0.));
#958=DIRECTION('',(-1.,0.,0.));
#959=AXIS2_PLACEMENT_3D('',#956,#957,#958);
#960=CIRCLE('',#959,1.5875);
#961=CARTESIAN_POINT('',(-1.58749999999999,-36.83,0.));
#962=VERTEX_POINT('',#961);
#963=EDGE_CURVE('E784',#962,#962,#960,.T.);
#964=ORIENTED_EDGE('',*,*,#963,.F.);
#965=EDGE_LOOP('',(#964));
#966=FACE_BOUND('',#965,.T.);
#967=ORIENTED_EDGE('',*,*,#943,.T.);
#968=EDGE_LOOP('',(#967));
#969=FACE_BOUND('',#968,.T.);
#970=ADVANCED_FACE('F743',(#966,#969),#955,.F.);
#971=CARTESIAN_POINT('',(-1.58749999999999,-36.83,0.));
#972=DIRECTION('',(0.,-1.,0.));
#973=DIRECTION('',(1.,0.,0.));
#974=AXIS2_PLACEMENT_3D('',#971,#972,#973);
#975=PLANE('',#974);
#976=CARTESIAN_POINT('',(0.,-36.83,0.));
#977=DIRECTION('',(0.,1.,0.));
#978=DIRECTION('',(-1.,0.,0.));
#979=AXIS2_PLACEMENT_3D('',#976,#977,#978);
#980=CIRCLE('',#979,1.27);
#981=CARTESIAN_POINT('',(-1.26999999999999,-36.83,0.));
#982=VERTEX_POINT('',#981);
#983=EDGE_CURVE('E783',#982,#982,#980,.T.);
#984=ORIENTED_EDGE('',*,*,#983,.F.);
#985=EDGE_LOOP('',(#984));
#986=FACE_BOUND('',#985,.T.);
#987=ORIENTED_EDGE('',*,*,#963,.T.);
#988=EDGE_LOOP('',(#987));
#989=FACE_BOUND('',#988,.T.);
#990=ADVANCED_FACE('F753',(#986,#989),#975,.F.);
#991=CARTESIAN_POINT('',(0.,15.3585913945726,0.));
#992=DIRECTION('',(0.,1.,0.));
#993=DIRECTION('',(-1.,0.,0.));
#994=AXIS2_PLACEMENT_3D('',#991,#992,#993);
#995=CYLINDRICAL_SURFACE('',#994,1.27);
#996=ORIENTED_EDGE('',*,*,#863,.F.);
#997=EDGE_LOOP('',(#996));
#998=FACE_BOUND('',#997,.T.);
#999=ORIENTED_EDGE('',*,*,#983,.T.);
#1000=EDGE_LOOP('',(#999));
#1001=FACE_BOUND('',#1000,.T.);
#1002=ADVANCED_FACE('F763',(#998,#1001),#995,.F.);
#1003=CLOSED_SHELL('',(#670,#690,#710,#730,#750,#770,#790,#810,#830,#850,#870,#898,#910,#930,
#950,#970,#990,#1002));
#1004=MANIFOLD_SOLID_BREP('B6',#1003);
#1005=CARTESIAN_POINT('',(9.16543552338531,8.89,0.));
#1006=DIRECTION('',(-0.866025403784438,0.,0.5));
#1007=DIRECTION('',(0.5,0.,0.866025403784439));
#1008=AXIS2_PLACEMENT_3D('',#1005,#1006,#1007);
#1009=PLANE('',#1008);
#1010=DIRECTION('',(-0.5,0.,-0.866025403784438));
#1011=VECTOR('',#1010,1.);
#1012=CARTESIAN_POINT('',(9.16543552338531,0.,0.));
#1013=LINE('',#1012,#1011);
#1014=CARTESIAN_POINT('',(9.16543552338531,0.,0.));
#1015=VERTEX_POINT('',#1014);
#1016=CARTESIAN_POINT('',(4.58271776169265,0.,-7.9375));
#1017=VERTEX_POINT('',#1016);
#1018=EDGE_CURVE('E905',#1015,#1017,#1013,.T.);
#1019=ORIENTED_EDGE('',*,*,#1018,.T.);
#1020=DIRECTION('',(0.,-1.,0.));
#1021=VECTOR('',#1020,1.);
#1022=CARTESIAN_POINT('',(4.58271776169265,8.89,-7.9375));
#1023=LINE('',#1022,#1021);
#1024=CARTESIAN_POINT('',(4.58271776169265,8.89,-7.9375));
#1025=VERTEX_POINT('',#1024);
#1026=EDGE_CURVE('E544',#1025,#1017,#1023,.T.);
#1027=ORIENTED_EDGE('',*,*,#1026,.F.);
#1028=DIRECTION('',(-0.5,0.,-0.866025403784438));
#1029=VECTOR('',#1028,1.);
#1030=CARTESIAN_POINT('',(9.16543552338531,8.89,0.));
#1031=LINE('',#1030,#1029);
#1032=CARTESIAN_POINT('',(9.16543552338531,8.89,0.));
#1033=VERTEX_POINT('',#1032);
#1034=EDGE_CURVE('E916',#1033,#1025,#1031,.T.);
#1035=ORIENTED_EDGE('',*,*,#1034,.F.);
#1036=DIRECTION('',(0.,-1.,0.));
#1037=VECTOR('',#1036,1.);
#1038=CARTESIAN_POINT('',(9.16543552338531,8.89,0.));
#1039=LINE('',#1038,#1037);
#1040=EDGE_CURVE('E901',#1033,#1015,#1039,.T.);
#1041=ORIENTED_EDGE('',*,*,#1040,.T.);
#1042=EDGE_LOOP('',(#1019,#1027,#1035,#1041));
#1043=FACE_BOUND('',#1042,.T.);
#1044=ADVANCED_FACE('F821',(#1043),#1009,.F.);
#1045=CARTESIAN_POINT('',(4.58271776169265,8.89,-7.9375));
#1046=DIRECTION('',(0.,0.,1.));
#1047=DIRECTION('',(1.,0.,0.));
#1048=AXIS2_PLACEMENT_3D('',#1045,#1046,#1047);
#1049=PLANE('',#1048);
#1050=DIRECTION('',(-1.,0.,0.));
#1051=VECTOR('',#1050,1.);
#1052=CARTESIAN_POINT('',(4.58271776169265,0.,-7.9375));
#1053=LINE('',#1052,#1051);
#1054=CARTESIAN_POINT('',(-4.58271776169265,0.,-7.9375));
#1055=VERTEX_POINT('',#1054);
#1056=EDGE_CURVE('E908',#1017,#1055,#1053,.T.);
#1057=ORIENTED_EDGE('',*,*,#1056,.T.);
#1058=DIRECTION('',(0.,-1.,0.));
#1059=VECTOR('',#1058,1.);
#1060=CARTESIAN_POINT('',(-4.58271776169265,8.89,-7.9375));
#1061=LINE('',#1060,#1059);
#1062=CARTESIAN_POINT('',(-4.58271776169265,8.89,-7.9375));
#1063=VERTEX_POINT('',#1062);
#1064=EDGE_CURVE('E829',#1063,#1055,#1061,.T.);
#1065=ORIENTED_EDGE('',*,*,#1064,.F.);
#1066=DIRECTION('',(-1.,0.,0.));
#1067=VECTOR('',#1066,1.);
#1068=CARTESIAN_POINT('',(4.58271776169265,8.89,-7.9375));
#1069=LINE('',#1068,#1067);
#1070=EDGE_CURVE('E874',#1025,#1063,#1069,.T.);
#1071=ORIENTED_EDGE('',*,*,#1070,.F.);
#1072=ORIENTED_EDGE('',*,*,#1026,.T.);
#1073=EDGE_LOOP('',(#1057,#1065,#1071,#1072));
#1074=FACE_BOUND('',#1073,.T.);
#1075=ADVANCED_FACE('F941',(#1074),#1049,.F.);
#1076=CARTESIAN_POINT('',(-4.58271776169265,8.89,-7.9375));
#1077=DIRECTION('',(0.866025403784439,0.,0.5));
#1078=DIRECTION('',(0.5,0.,-0.866025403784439));
#1079=AXIS2_PLACEMENT_3D('',#1076,#1077,#1078);
#1080=PLANE('',#1079);
#1081=DIRECTION('',(-0.5,0.,0.866025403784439));
#1082=VECTOR('',#1081,1.);
#1083=CARTESIAN_POINT('',(-4.58271776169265,0.,-7.9375));
#1084=LINE('',#1083,#1082);
#1085=CARTESIAN_POINT('',(-9.16543552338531,0.,0.));
#1086=VERTEX_POINT('',#1085);
#1087=EDGE_CURVE('E911',#1055,#1086,#1084,.T.);
#1088=ORIENTED_EDGE('',*,*,#1087,.T.);
#1089=DIRECTION('',(0.,-1.,0.));
#1090=VECTOR('',#1089,1.);
#1091=CARTESIAN_POINT('',(-9.16543552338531,8.89,0.));
#1092=LINE('',#1091,#1090);
#1093=CARTESIAN_POINT('',(-9.16543552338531,8.89,0.));
#1094=VERTEX_POINT('',#1093);
#1095=EDGE_CURVE('E896',#1094,#1086,#1092,.T.);
#1096=ORIENTED_EDGE('',*,*,#1095,.F.);
#1097=DIRECTION('',(-0.5,0.,0.866025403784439));
#1098=VECTOR('',#1097,1.);
#1099=CARTESIAN_POINT('',(-4.58271776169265,8.89,-7.9375));
#1100=LINE('',#1099,#1098);
#1101=EDGE_CURVE('E887',#1063,#1094,#1100,.T.);
#1102=ORIENTED_EDGE('',*,*,#1101,.F.);
#1103=ORIENTED_EDGE('',*,*,#1064,.T.);
#1104=EDGE_LOOP('',(#1088,#1096,#1102,#1103));
#1105=FACE_BOUND('',#1104,.T.);
#1106=ADVANCED_FACE('F922',(#1105),#1080,.F.);
#1107=CARTESIAN_POINT('',(-9.16543552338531,8.89,0.));
#1108=DIRECTION('',(0.866025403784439,0.,-0.5));
#1109=DIRECTION('',(-0.5,0.,-0.866025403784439));
#1110=AXIS2_PLACEMENT_3D('',#1107,#1108,#1109);
#1111=PLANE('',#1110);
#1112=DIRECTION('',(0.5,0.,0.866025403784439));
#1113=VECTOR('',#1112,1.);
#1114=CARTESIAN_POINT('',(-9.16543552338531,0.,0.));
#1115=LINE('',#1114,#1113);
#1116=CARTESIAN_POINT('',(-4.58271776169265,0.,7.9375));
#1117=VERTEX_POINT('',#1116);
#1118=EDGE_CURVE('E895',#1086,#1117,#1115,.T.);
#1119=ORIENTED_EDGE('',*,*,#1118,.T.);
#1120=DIRECTION('',(0.,-1.,0.));
#1121=VECTOR('',#1120,1.);
#1122=CARTESIAN_POINT('',(-4.58271776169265,8.89,7.9375));
#1123=LINE('',#1122,#1121);
#1124=CARTESIAN_POINT('',(-4.58271776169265,8.89,7.9375));
#1125=VERTEX_POINT('',#1124);
#1126=EDGE_CURVE('E892',#1125,#1117,#1123,.T.);
#1127=ORIENTED_EDGE('',*,*,#1126,.F.);
#1128=DIRECTION('',(0.5,0.,0.866025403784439));
#1129=VECTOR('',#1128,1.);
#1130=CARTESIAN_POINT('',(-9.16543552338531,8.89,0.));
#1131=LINE('',#1130,#1129);
#1132=EDGE_CURVE('E881',#1094,#1125,#1131,.T.);
#1133=ORIENTED_EDGE('',*,*,#1132,.F.);
#1134=ORIENTED_EDGE('',*,*,#1095,.T.);
#1135=EDGE_LOOP('',(#1119,#1127,#1133,#1134));
#1136=FACE_BOUND('',#1135,.T.);
#1137=ADVANCED_FACE('F893',(#1136),#1111,.F.);
#1138=CARTESIAN_POINT('',(-4.58271776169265,8.89,7.9375));
#1139=DIRECTION('',(0.,0.,-1.));
#1140=DIRECTION('',(-1.,0.,0.));
#1141=AXIS2_PLACEMENT_3D('',#1138,#1139,#1140);
#1142=PLANE('',#1141);
#1143=DIRECTION('',(1.,0.,0.));
#1144=VECTOR('',#1143,1.);
#1145=CARTESIAN_POINT('',(-4.58271776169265,0.,7.9375));
#1146=LINE('',#1145,#1144);
#1147=CARTESIAN_POINT('',(4.58271776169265,0.,7.9375));
#1148=VERTEX_POINT('',#1147);
#1149=EDGE_CURVE('E860',#1117,#1148,#1146,.T.);
#1150=ORIENTED_EDGE('',*,*,#1149,.T.);
#1151=DIRECTION('',(0.,-1.,0.));
#1152=VECTOR('',#1151,1.);
#1153=CARTESIAN_POINT('',(4.58271776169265,8.89,7.9375));
#1154=LINE('',#1153,#1152);
#1155=CARTESIAN_POINT('',(4.58271776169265,8.89,7.9375));
#1156=VERTEX_POINT('',#1155);
#1157=EDGE_CURVE('E897',#1156,#1148,#1154,.T.);
#1158=ORIENTED_EDGE('',*,*,#1157,.F.);
#1159=DIRECTION('',(1.,0.,0.));
#1160=VECTOR('',#1159,1.);
#1161=CARTESIAN_POINT('',(-4.58271776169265,8.89,7.9375));
#1162=LINE('',#1161,#1160);
#1163=EDGE_CURVE('E885',#1125,#1156,#1162,.T.);
#1164=ORIENTED_EDGE('',*,*,#1163,.F.);
#1165=ORIENTED_EDGE('',*,*,#1126,.T.);
#1166=EDGE_LOOP('',(#1150,#1158,#1164,#1165));
#1167=FACE_BOUND('',#1166,.T.);
#1168=ADVANCED_FACE('F899',(#1167),#1142,.F.);
#1169=CARTESIAN_POINT('',(4.58271776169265,8.89,7.9375));
#1170=DIRECTION('',(-0.866025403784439,0.,-0.5));
#1171=DIRECTION('',(-0.5,0.,0.866025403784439));
#1172=AXIS2_PLACEMENT_3D('',#1169,#1170,#1171);
#1173=PLANE('',#1172);
#1174=DIRECTION('',(0.5,0.,-0.866025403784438));
#1175=VECTOR('',#1174,1.);
#1176=CARTESIAN_POINT('',(4.58271776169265,0.,7.9375));
#1177=LINE('',#1176,#1175);
#1178=EDGE_CURVE('E866',#1148,#1015,#1177,.T.);
#1179=ORIENTED_EDGE('',*,*,#1178,.T.);
#1180=ORIENTED_EDGE('',*,*,#1040,.F.);
#1181=DIRECTION('',(0.5,0.,-0.866025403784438));
#1182=VECTOR('',#1181,1.);
#1183=CARTESIAN_POINT('',(4.58271776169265,8.89,7.9375));
#1184=LINE('',#1183,#1182);
#1185=EDGE_CURVE('E837',#1156,#1033,#1184,.T.);
#1186=ORIENTED_EDGE('',*,*,#1185,.F.);
#1187=ORIENTED_EDGE('',*,*,#1157,.T.);
#1188=EDGE_LOOP('',(#1179,#1180,#1186,#1187));
#1189=FACE_BOUND('',#1188,.T.);
#1190=ADVANCED_FACE('F929',(#1189),#1173,.F.);
#1191=CARTESIAN_POINT('',(0.,8.89,0.));
#1192=DIRECTION('',(0.,1.,0.));
#1193=DIRECTION('',(0.,0.,1.));
#1194=AXIS2_PLACEMENT_3D('',#1191,#1192,#1193);
#1195=PLANE('',#1194);
#1196=CARTESIAN_POINT('',(0.,8.89,0.));
#1197=DIRECTION('',(0.,1.,0.));
#1198=DIRECTION('',(0.,0.,1.));
#1199=AXIS2_PLACEMENT_3D('',#1196,#1197,#1198);
#1200=CIRCLE('',#1199,3.4544);
#1201=CARTESIAN_POINT('',(0.,8.89,3.4544));
#1202=VERTEX_POINT('',#1201);
#1203=EDGE_CURVE('E996',#1202,#1202,#1200,.T.);
#1204=ORIENTED_EDGE('',*,*,#1203,.F.);
#1205=EDGE_LOOP('',(#1204));
#1206=FACE_BOUND('',#1205,.T.);
#1207=ORIENTED_EDGE('',*,*,#1034,.T.);
#1208=ORIENTED_EDGE('',*,*,#1070,.T.);
#1209=ORIENTED_EDGE('',*,*,#1101,.T.);
#1210=ORIENTED_EDGE('',*,*,#1132,.T.);
#1211=ORIENTED_EDGE('',*,*,#1163,.T.);
#1212=ORIENTED_EDGE('',*,*,#1185,.T.);
#1213=EDGE_LOOP('',(#1207,#1208,#1209,#1210,#1211,#1212));
#1214=FACE_BOUND('',#1213,.T.);
#1215=ADVANCED_FACE('F883',(#1206,#1214),#1195,.T.);
#1216=CARTESIAN_POINT('',(0.,0.,0.));
#1217=DIRECTION('',(0.,1.,0.));
#1218=DIRECTION('',(0.,0.,1.));
#1219=AXIS2_PLACEMENT_3D('',#1216,#1217,#1218);
#1220=PLANE('',#1219);
#1221=CARTESIAN_POINT('',(0.,0.,0.));
#1222=DIRECTION('',(0.,1.,0.));
#1223=DIRECTION('',(0.,0.,1.));
#1224=AXIS2_PLACEMENT_3D('',#1221,#1222,#1223);
#1225=CIRCLE('',#1224,3.4544);
#1226=CARTESIAN_POINT('',(0.,0.,3.4544));
#1227=VERTEX_POINT('',#1226);
#1228=EDGE_CURVE('E909',#1227,#1227,#1225,.T.);
#1229=ORIENTED_EDGE('',*,*,#1228,.T.);
#1230=EDGE_LOOP('',(#1229));
#1231=FACE_BOUND('',#1230,.T.);
#1232=ORIENTED_EDGE('',*,*,#1018,.F.);
#1233=ORIENTED_EDGE('',*,*,#1178,.F.);
#1234=ORIENTED_EDGE('',*,*,#1149,.F.);
#1235=ORIENTED_EDGE('',*,*,#1118,.F.);
#1236=ORIENTED_EDGE('',*,*,#1087,.F.);
#1237=ORIENTED_EDGE('',*,*,#1056,.F.);
#1238=EDGE_LOOP('',(#1232,#1233,#1234,#1235,#1236,#1237));
#1239=FACE_BOUND('',#1238,.T.);
#1240=ADVANCED_FACE('F925',(#1231,#1239),#1220,.F.);
#1241=CARTESIAN_POINT('',(0.,8.89,0.));
#1242=DIRECTION('',(0.,1.,0.));
#1243=DIRECTION('',(0.,0.,1.));
#1244=AXIS2_PLACEMENT_3D('',#1241,#1242,#1243);
#1245=CYLINDRICAL_SURFACE('',#1244,3.4544);
#1246=ORIENTED_EDGE('',*,*,#1203,.T.);
#1247=EDGE_LOOP('',(#1246));
#1248=FACE_BOUND('',#1247,.T.);
#1249=ORIENTED_EDGE('',*,*,#1228,.F.);
#1250=EDGE_LOOP('',(#1249));
#1251=FACE_BOUND('',#1250,.T.);
#1252=ADVANCED_FACE('F978',(#1248,#1251),#1245,.F.);
#1253=CLOSED_SHELL('',(#1044,#1075,#1106,#1137,#1168,#1190,#1215,#1240,#1252));
#1254=MANIFOLD_SOLID_BREP('B39',#1253);
#1255=ADVANCED_BREP_SHAPE_REPRESENTATION('',(#18,#642,#1004,#1254),#14);
#1256=SHAPE_DEFINITION_REPRESENTATION(#9,#1255);
ENDSEC;
END-ISO-10303-21;
